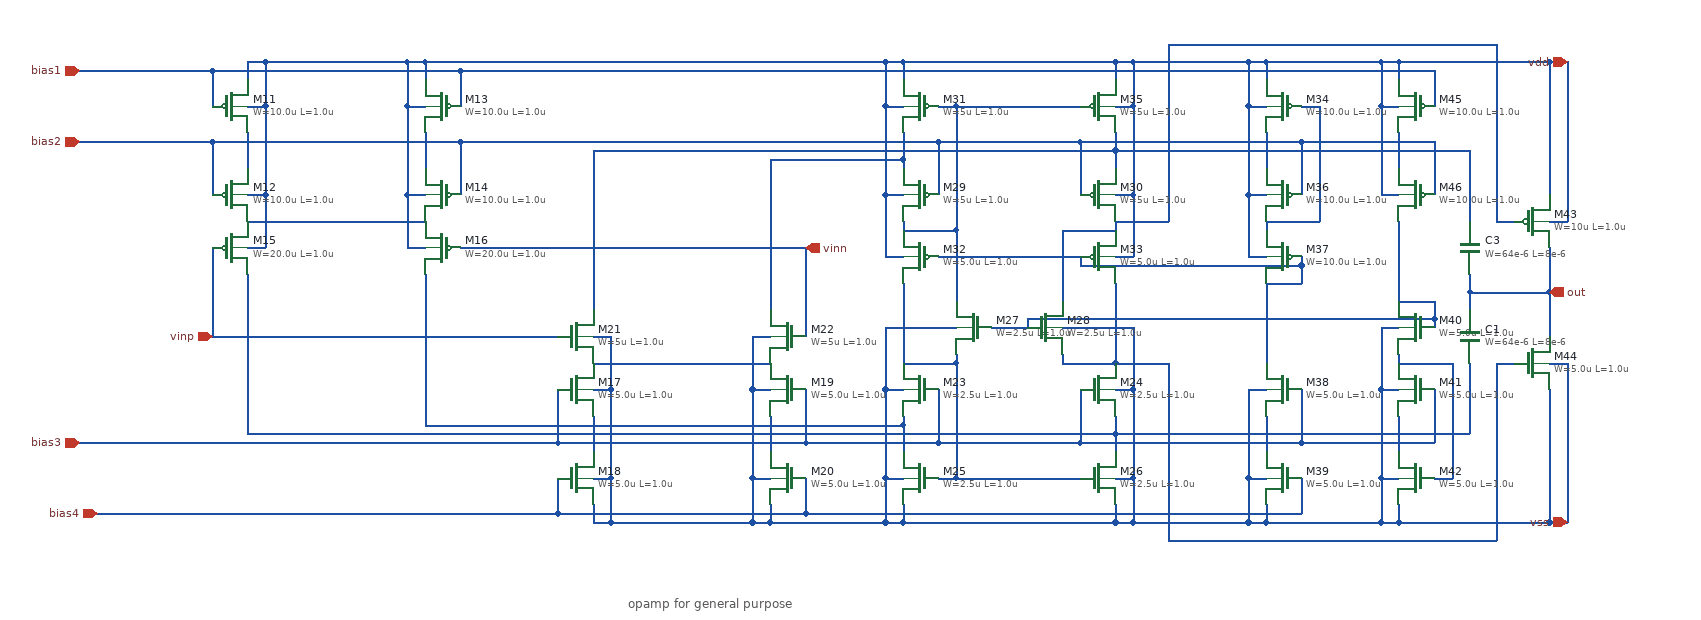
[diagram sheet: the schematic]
v {xschem version=3.4.7 file_version=1.2}
G {}
K {}
V {}
S {}
E {}
T {opamp for general purpose} 1180 0 2 0 0.4 0.4 {}
N 750 -390 770 -390 {
lab=vdd}
N 930 -390 950 -390 {
lab=vdd}
N 750 -600 750 -580 {
lab=vdd}
N 750 -550 770 -550 {
lab=vdd}
N 710 -590 710 -550 {
lab=bias1}
N 1470 -130 1470 -80 {
lab=vss}
N 1470 -130 1490 -130 {
lab=vss}
N 1490 -100 1490 -80 {
lab=vss}
N 1490 -600 1490 -580 {
lab=vdd}
N 1470 -550 1490 -550 {
lab=vdd}
N 1730 -600 1730 -580 {
lab=vdd}
N 1730 -550 1750 -550 {
lab=vdd}
N 1750 -550 1750 -450 {
lab=vdd}
N 1730 -130 1750 -130 {
lab=vss}
N 1730 -100 1730 -80 {
lab=vss}
N 710 -390 710 -290 {
lab=vinp}
N 1320 -290 1340 -290 {
lab=vss}
N 1140 -230 1160 -230 {
lab=vss}
N 1160 -130 1160 -80 {
lab=vss}
N 1140 -130 1160 -130 {
lab=vss}
N 1140 -200 1140 -160 {
lab=#net1}
N 1140 -100 1140 -80 {
lab=vss}
N 1100 -130 1100 -90 {
lab=bias4}
N 1100 -230 1100 -170 {
lab=bias3}
N 750 -450 770 -450 {
lab=vdd}
N 750 -520 750 -480 {
lab=#net2}
N 710 -510 710 -450 {
lab=bias2}
N 1470 -550 1470 -450 {
lab=vdd}
N 1470 -450 1490 -450 {
lab=vdd}
N 1490 -490 1490 -480 {
lab=#net3}
N 1470 -230 1490 -230 {
lab=vss}
N 1470 -230 1470 -130 {
lab=vss}
N 1490 -190 1490 -160 {
lab=#net4}
N 1730 -180 1730 -160 {
lab=#net5}
N 1730 -230 1750 -230 {
lab=vss}
N 990 -390 1380 -390 {
lab=vinn}
N 1380 -390 1380 -290 {
lab=vinn}
N 1730 -450 1750 -450 {
lab=vdd}
N 1730 -500 1730 -480 {
lab=#net6}
N 750 -420 950 -420 {
lab=#net7}
N 710 -290 1100 -290 {
lab=vinp}
N 1140 -260 1340 -260 {
lab=#net8}
N 1490 -420 1490 -410 {
lab=#net9}
N 1470 -380 1490 -380 {
lab=vdd}
N 1470 -450 1470 -380 {
lab=vdd}
N 1550 -130 1690 -130 {
lab=#net10}
N 1750 -130 1750 -80 {
lab=vss}
N 1590 -300 1630 -300 {
lab=#net11}
N 1730 -380 1750 -380 {
lab=vdd}
N 1750 -450 1750 -380 {
lab=vdd}
N 1730 -420 1730 -410 {
lab=#net12}
N 1670 -300 1750 -300 {
lab=vss}
N 1750 -300 1750 -230 {
lab=vss}
N 2220 -340 2220 -290 {
lab=out}
N 2220 -420 2240 -420 {
lab=vdd}
N 2240 -600 2240 -420 {
lab=vdd}
N 1900 -600 2030 -600 {
lab=vdd}
N 2220 -260 2240 -260 {
lab=vss}
N 2240 -260 2240 -80 {
lab=vss}
N 2220 -230 2220 -80 {
lab=vss}
N 2220 -600 2220 -450 {
lab=vdd}
N 1880 -550 1900 -550 {
lab=vdd}
N 1880 -600 1880 -550 {
lab=vdd}
N 1900 -600 1900 -580 {
lab=vdd}
N 1900 -520 1900 -480 {
lab=#net13}
N 1880 -450 1900 -450 {
lab=vdd}
N 1880 -550 1880 -450 {
lab=vdd}
N 1900 -420 1900 -410 {
lab=#net14}
N 1880 -380 1900 -380 {
lab=vdd}
N 1880 -450 1880 -380 {
lab=vdd}
N 1880 -230 1900 -230 {
lab=vss}
N 1880 -130 1880 -80 {
lab=vss}
N 1880 -130 1900 -130 {
lab=vss}
N 1900 -200 1900 -160 {
lab=#net15}
N 1900 -100 1900 -80 {
lab=vss}
N 1940 -130 1940 -90 {
lab=bias4}
N 1940 -230 1940 -170 {
lab=bias3}
N 2030 -550 2050 -550 {
lab=vdd}
N 2030 -600 2030 -550 {
lab=vdd}
N 2050 -600 2050 -580 {
lab=vdd}
N 2050 -520 2050 -480 {
lab=#net16}
N 2030 -450 2050 -450 {
lab=vdd}
N 2030 -550 2030 -450 {
lab=vdd}
N 2030 -230 2050 -230 {
lab=vss}
N 2030 -130 2030 -80 {
lab=vss}
N 2030 -130 2050 -130 {
lab=vss}
N 2050 -200 2050 -160 {
lab=#net17}
N 2050 -100 2050 -80 {
lab=vss}
N 2050 -270 2050 -260 {
lab=#net18}
N 2030 -300 2050 -300 {
lab=vss}
N 2030 -300 2030 -230 {
lab=vss}
N 2050 -600 2220 -600 {
lab=vdd}
N 950 -600 950 -580 {
lab=vdd}
N 930 -550 950 -550 {
lab=vdd}
N 990 -590 990 -550 {
lab=bias1}
N 930 -450 950 -450 {
lab=vdd}
N 950 -520 950 -480 {
lab=#net19}
N 990 -510 990 -450 {
lab=bias2}
N 1320 -230 1340 -230 {
lab=vss}
N 1320 -130 1340 -130 {
lab=vss}
N 1340 -200 1340 -160 {
lab=#net20}
N 1340 -100 1340 -80 {
lab=vss}
N 1380 -130 1380 -90 {
lab=bias4}
N 1380 -230 1380 -170 {
lab=bias3}
N 1140 -290 1160 -290 {
lab=vss}
N 1940 -510 1940 -450 {
lab=bias2}
N 1940 -550 1960 -550 {
lab=#net14}
N 1960 -550 1960 -420 {
lab=#net14}
N 1900 -420 1960 -420 {
lab=#net14}
N 1940 -370 1940 -350 {
lab=#net21}
N 1900 -350 1940 -350 {
lab=#net21}
N 1900 -350 1900 -260 {
lab=#net21}
N 2090 -590 2090 -550 {
lab=bias1}
N 2090 -510 2090 -450 {
lab=bias2}
N 1690 -170 1940 -170 {
lab=bias3}
N 2090 -230 2090 -170 {
lab=bias3}
N 2090 -130 2110 -130 {
lab=#net18}
N 2110 -260 2110 -130 {
lab=#net18}
N 2050 -260 2110 -260 {
lab=#net18}
N 2090 -310 2090 -300 {
lab=#net11}
N 2050 -330 2090 -330 {
lab=#net11}
N 2050 -420 2050 -330 {
lab=#net11}
N 1550 -550 1690 -550 {
lab=#net9}
N 1530 -510 1530 -450 {
lab=bias2}
N 1690 -510 1690 -450 {
lab=bias2}
N 1530 -380 1690 -380 {
lab=#net21}
N 1490 -350 1490 -260 {
lab=#net10}
N 1550 -270 1550 -260 {
lab=#net10}
N 1490 -260 1550 -260 {
lab=#net10}
N 1670 -270 1670 -260 {
lab=#net22}
N 1670 -260 1730 -260 {
lab=#net22}
N 1470 -300 1550 -300 {
lab=vss}
N 1470 -300 1470 -230 {
lab=vss}
N 1730 -350 1730 -260 {
lab=#net22}
N 1550 -410 1550 -330 {
lab=#net9}
N 1490 -410 1550 -410 {
lab=#net9}
N 1670 -410 1670 -330 {
lab=#net12}
N 1670 -410 1730 -410 {
lab=#net12}
N 1940 -510 2090 -510 {
lab=bias2}
N 1380 -90 1940 -90 {
lab=bias4}
N 1940 -170 2090 -170 {
lab=bias3}
N 1690 -370 1940 -370 {
lab=#net21}
N 1690 -380 1690 -370 {
lab=#net21}
N 1630 -310 2090 -310 {
lab=#net11}
N 1630 -310 1630 -300 {
lab=#net11}
N 750 -360 750 -180 {
lab=#net5}
N 950 -360 950 -190 {
lab=#net4}
N 1140 -500 1140 -320 {
lab=#net6}
N 1340 -490 1340 -320 {
lab=#net3}
N 1530 -230 1530 -170 {
lab=bias3}
N 1690 -230 1690 -170 {
lab=bias3}
N 1550 -260 1550 -130 {
lab=#net10}
N 1550 -550 1550 -410 {
lab=#net9}
N 2220 -600 2240 -600 {
lab=vdd}
N 2160 -420 2180 -420 {
lab=#net12}
N 2160 -620 2160 -420 {
lab=#net12}
N 1790 -620 2160 -620 {
lab=#net12}
N 1790 -620 1790 -420 {
lab=#net12}
N 1730 -420 1790 -420 {
lab=#net12}
N 2160 -260 2180 -260 {
lab=#net22}
N 2160 -260 2160 -60 {
lab=#net22}
N 1790 -60 2160 -60 {
lab=#net22}
N 1790 -260 1790 -60 {
lab=#net22}
N 1730 -260 1790 -260 {
lab=#net22}
N 1730 -180 2130 -180 {
lab=#net5}
N 2130 -340 2130 -320 {
lab=out}
N 1140 -500 1730 -500 {
lab=#net6}
N 1340 -490 1490 -490 {
lab=#net3}
N 950 -190 1490 -190 {
lab=#net4}
N 750 -180 1730 -180 {
lab=#net5}
N 1470 -600 1490 -600 {
lab=vdd}
N 1730 -600 1750 -600 {
lab=vdd}
N 2220 -80 2240 -80 {
lab=vss}
N 1100 -170 1380 -170 {
lab=bias3}
N 1100 -90 1380 -90 {
lab=bias4}
N 710 -590 990 -590 {
lab=bias1}
N 710 -510 990 -510 {
lab=bias2}
N 1690 -510 1940 -510 {
lab=bias2}
N 990 -590 2090 -590 {
lab=bias1}
N 930 -600 950 -600 {
lab=vdd}
N 560 -590 710 -590 {
lab=bias1}
N 560 -510 710 -510 {
lab=bias2}
N 560 -170 1100 -170 {
lab=bias3}
N 580 -90 1100 -90 {
lab=bias4}
N 2130 -340 2220 -340 {
lab=out}
N 2130 -260 2130 -180 {
lab=#net5}
N 1730 -500 2130 -500 {
lab=#net6}
N 2130 -500 2130 -420 {
lab=#net6}
N 2130 -360 2130 -340 {
lab=out}
N 930 -550 930 -450 {
lab=vdd}
N 770 -550 770 -450 {
lab=vdd}
N 1320 -130 1320 -80 {
lab=vss}
N 1160 -290 1160 -230 {
lab=vss}
N 1320 -290 1320 -230 {
lab=vss}
N 770 -450 770 -390 {
lab=vdd}
N 930 -450 930 -390 {
lab=vdd}
N 770 -600 770 -550 {
lab=vdd}
N 1340 -80 1470 -80 {
lab=vss}
N 1470 -80 1490 -80 {
lab=vss}
N 1470 -600 1470 -550 {
lab=vdd}
N 1490 -600 1730 -600 {
lab=vdd}
N 1750 -600 1750 -550 {
lab=vdd}
N 1750 -230 1750 -130 {
lab=vss}
N 1490 -80 1730 -80 {
lab=vss}
N 1140 -80 1160 -80 {
lab=vss}
N 1160 -230 1160 -130 {
lab=vss}
N 1730 -80 1750 -80 {
lab=vss}
N 2050 -80 2220 -80 {
lab=vss}
N 1750 -600 1880 -600 {
lab=vdd}
N 1880 -600 1900 -600 {
lab=vdd}
N 1750 -80 1880 -80 {
lab=vss}
N 1880 -230 1880 -130 {
lab=vss}
N 1880 -80 1900 -80 {
lab=vss}
N 2030 -600 2050 -600 {
lab=vdd}
N 1900 -80 2030 -80 {
lab=vss}
N 2030 -230 2030 -130 {
lab=vss}
N 2030 -80 2050 -80 {
lab=vss}
N 930 -600 930 -550 {
lab=vdd}
N 1320 -230 1320 -130 {
lab=vss}
N 1320 -80 1340 -80 {
lab=vss}
N 990 -510 1530 -510 {
lab=bias2}
N 1530 -510 1690 -510 {
lab=bias2}
N 1940 -380 1940 -370 {
lab=#net21}
N 2090 -330 2090 -310 {
lab=#net11}
N 1380 -170 1530 -170 {
lab=bias3}
N 1530 -170 1690 -170 {
lab=bias3}
N 1530 -130 1550 -130 {
lab=#net10}
N 1530 -550 1550 -550 {
lab=#net9}
N 1730 -200 1730 -180 {
lab=#net5}
N 1730 -520 1730 -500 {
lab=#net6}
N 1490 -520 1490 -490 {
lab=#net3}
N 1490 -200 1490 -190 {
lab=#net4}
N 2220 -390 2220 -340 {
lab=out}
N 1160 -80 1320 -80 {
lab=vss}
N 750 -600 770 -600 {
lab=vdd}
N 950 -600 1470 -600 {
lab=vdd}
N 770 -600 930 -600 {
lab=vdd}
C {devices/opin.sym} 2220 -340 0 0 {name=p1 lab=out}
C {devices/iopin.sym} 2240 -600 0 0 {name=p3 lab=vdd}
C {devices/iopin.sym} 2240 -80 0 0 {name=p4 lab=vss}
C {devices/ipin.sym} 710 -290 0 0 {name=p2 lab=vinp}
C {devices/ipin.sym} 1380 -390 0 1 {name=p5 lab=vinn}
C {symbols/pfet_06v0.sym} 730 -550 0 0 {name=M11
L=1.0u
W=10.0u
nf=1
m=1
ad="'int((nf+1)/2) * W/nf * 0.18u'"
pd="'2*int((nf+1)/2) * (W/nf + 0.18u)'"
as="'int((nf+2)/2) * W/nf * 0.18u'"
ps="'2*int((nf+2)/2) * (W/nf + 0.18u)'"
nrd="'0.18u / W'" nrs="'0.18u / W'"
sa=0 sb=0 sd=0
model=pfet_06v0
spiceprefix=X
}
C {symbols/pfet_06v0.sym} 730 -450 0 0 {name=M12
L=1.0u
W=10.0u
nf=1
m=1
ad="'int((nf+1)/2) * W/nf * 0.18u'"
pd="'2*int((nf+1)/2) * (W/nf + 0.18u)'"
as="'int((nf+2)/2) * W/nf * 0.18u'"
ps="'2*int((nf+2)/2) * (W/nf + 0.18u)'"
nrd="'0.18u / W'" nrs="'0.18u / W'"
sa=0 sb=0 sd=0
model=pfet_06v0
spiceprefix=X
}
C {symbols/pfet_06v0.sym} 970 -550 0 1 {name=M13
L=1.0u
W=10.0u
nf=1
m=1
ad="'int((nf+1)/2) * W/nf * 0.18u'"
pd="'2*int((nf+1)/2) * (W/nf + 0.18u)'"
as="'int((nf+2)/2) * W/nf * 0.18u'"
ps="'2*int((nf+2)/2) * (W/nf + 0.18u)'"
nrd="'0.18u / W'" nrs="'0.18u / W'"
sa=0 sb=0 sd=0
model=pfet_06v0
spiceprefix=X
}
C {symbols/pfet_06v0.sym} 970 -450 0 1 {name=M14
L=1.0u
W=10.0u
nf=1
m=1
ad="'int((nf+1)/2) * W/nf * 0.18u'"
pd="'2*int((nf+1)/2) * (W/nf + 0.18u)'"
as="'int((nf+2)/2) * W/nf * 0.18u'"
ps="'2*int((nf+2)/2) * (W/nf + 0.18u)'"
nrd="'0.18u / W'" nrs="'0.18u / W'"
sa=0 sb=0 sd=0
model=pfet_06v0
spiceprefix=X
}
C {symbols/pfet_06v0.sym} 730 -390 0 0 {name=M15
L=1.0u
W=20.0u
nf=2
m=1
ad="'int((nf+1)/2) * W/nf * 0.18u'"
pd="'2*int((nf+1)/2) * (W/nf + 0.18u)'"
as="'int((nf+2)/2) * W/nf * 0.18u'"
ps="'2*int((nf+2)/2) * (W/nf + 0.18u)'"
nrd="'0.18u / W'" nrs="'0.18u / W'"
sa=0 sb=0 sd=0
model=pfet_06v0
spiceprefix=X
}
C {symbols/pfet_06v0.sym} 970 -390 0 1 {name=M16
L=1.0u
W=20.0u
nf=2
m=1
ad="'int((nf+1)/2) * W/nf * 0.18u'"
pd="'2*int((nf+1)/2) * (W/nf + 0.18u)'"
as="'int((nf+2)/2) * W/nf * 0.18u'"
ps="'2*int((nf+2)/2) * (W/nf + 0.18u)'"
nrd="'0.18u / W'" nrs="'0.18u / W'"
sa=0 sb=0 sd=0
model=pfet_06v0
spiceprefix=X
}
C {symbols/nfet_06v0.sym} 1120 -230 0 0 {name=M17
L=1.0u
W=5.0u
nf=1
m=1
ad="'int((nf+1)/2) * W/nf * 0.18u'"
pd="'2*int((nf+1)/2) * (W/nf + 0.18u)'"
as="'int((nf+2)/2) * W/nf * 0.18u'"
ps="'2*int((nf+2)/2) * (W/nf + 0.18u)'"
nrd="'0.18u / W'" nrs="'0.18u / W'"
sa=0 sb=0 sd=0
model=nfet_06v0
spiceprefix=X
}
C {symbols/nfet_06v0.sym} 1120 -130 0 0 {name=M18
L=1.0u
W=5.0u
nf=1
m=1
ad="'int((nf+1)/2) * W/nf * 0.18u'"
pd="'2*int((nf+1)/2) * (W/nf + 0.18u)'"
as="'int((nf+2)/2) * W/nf * 0.18u'"
ps="'2*int((nf+2)/2) * (W/nf + 0.18u)'"
nrd="'0.18u / W'" nrs="'0.18u / W'"
sa=0 sb=0 sd=0
model=nfet_06v0
spiceprefix=X
}
C {symbols/nfet_06v0.sym} 1360 -230 0 1 {name=M19
L=1.0u
W=5.0u
nf=1
m=1
ad="'int((nf+1)/2) * W/nf * 0.18u'"
pd="'2*int((nf+1)/2) * (W/nf + 0.18u)'"
as="'int((nf+2)/2) * W/nf * 0.18u'"
ps="'2*int((nf+2)/2) * (W/nf + 0.18u)'"
nrd="'0.18u / W'" nrs="'0.18u / W'"
sa=0 sb=0 sd=0
model=nfet_06v0
spiceprefix=X
}
C {symbols/nfet_06v0.sym} 1360 -130 0 1 {name=M20
L=1.0u
W=5.0u
nf=1
m=1
ad="'int((nf+1)/2) * W/nf * 0.18u'"
pd="'2*int((nf+1)/2) * (W/nf + 0.18u)'"
as="'int((nf+2)/2) * W/nf * 0.18u'"
ps="'2*int((nf+2)/2) * (W/nf + 0.18u)'"
nrd="'0.18u / W'" nrs="'0.18u / W'"
sa=0 sb=0 sd=0
model=nfet_06v0
spiceprefix=X
}
C {symbols/nfet_06v0.sym} 1120 -290 0 0 {name=M21
L=1.0u
W=5u
nf=2
m=1
ad="'int((nf+1)/2) * W/nf * 0.18u'"
pd="'2*int((nf+1)/2) * (W/nf + 0.18u)'"
as="'int((nf+2)/2) * W/nf * 0.18u'"
ps="'2*int((nf+2)/2) * (W/nf + 0.18u)'"
nrd="'0.18u / W'" nrs="'0.18u / W'"
sa=0 sb=0 sd=0
model=nfet_06v0
spiceprefix=X
}
C {symbols/nfet_06v0.sym} 1360 -290 0 1 {name=M22
L=1.0u
W=5u
nf=2
m=1
ad="'int((nf+1)/2) * W/nf * 0.18u'"
pd="'2*int((nf+1)/2) * (W/nf + 0.18u)'"
as="'int((nf+2)/2) * W/nf * 0.18u'"
ps="'2*int((nf+2)/2) * (W/nf + 0.18u)'"
nrd="'0.18u / W'" nrs="'0.18u / W'"
sa=0 sb=0 sd=0
model=nfet_06v0
spiceprefix=X
}
C {symbols/pfet_06v0.sym} 1510 -450 0 1 {name=M29
L=1.0u
W=5u
nf=2
m=1
ad="'int((nf+1)/2) * W/nf * 0.18u'"
pd="'2*int((nf+1)/2) * (W/nf + 0.18u)'"
as="'int((nf+2)/2) * W/nf * 0.18u'"
ps="'2*int((nf+2)/2) * (W/nf + 0.18u)'"
nrd="'0.18u / W'" nrs="'0.18u / W'"
sa=0 sb=0 sd=0
model=pfet_06v0
spiceprefix=X
}
C {symbols/pfet_06v0.sym} 1710 -450 0 0 {name=M30
L=1.0u
W=5u
nf=2
m=1
ad="'int((nf+1)/2) * W/nf * 0.18u'"
pd="'2*int((nf+1)/2) * (W/nf + 0.18u)'"
as="'int((nf+2)/2) * W/nf * 0.18u'"
ps="'2*int((nf+2)/2) * (W/nf + 0.18u)'"
nrd="'0.18u / W'" nrs="'0.18u / W'"
sa=0 sb=0 sd=0
model=pfet_06v0
spiceprefix=X
}
C {symbols/pfet_06v0.sym} 1510 -550 0 1 {name=M31
L=1.0u
W=5u
nf=4
m=1
ad="'int((nf+1)/2) * W/nf * 0.18u'"
pd="'2*int((nf+1)/2) * (W/nf + 0.18u)'"
as="'int((nf+2)/2) * W/nf * 0.18u'"
ps="'2*int((nf+2)/2) * (W/nf + 0.18u)'"
nrd="'0.18u / W'" nrs="'0.18u / W'"
sa=0 sb=0 sd=0
model=pfet_06v0
spiceprefix=X
}
C {symbols/pfet_06v0.sym} 1710 -550 0 0 {name=M35
L=1.0u
W=5u
nf=4
m=1
ad="'int((nf+1)/2) * W/nf * 0.18u'"
pd="'2*int((nf+1)/2) * (W/nf + 0.18u)'"
as="'int((nf+2)/2) * W/nf * 0.18u'"
ps="'2*int((nf+2)/2) * (W/nf + 0.18u)'"
nrd="'0.18u / W'" nrs="'0.18u / W'"
sa=0 sb=0 sd=0
model=pfet_06v0
spiceprefix=X
}
C {symbols/pfet_06v0.sym} 1510 -380 0 1 {name=M32
L=1.0u
W=5.0u
nf=2
m=1
ad="'int((nf+1)/2) * W/nf * 0.18u'"
pd="'2*int((nf+1)/2) * (W/nf + 0.18u)'"
as="'int((nf+2)/2) * W/nf * 0.18u'"
ps="'2*int((nf+2)/2) * (W/nf + 0.18u)'"
nrd="'0.18u / W'" nrs="'0.18u / W'"
sa=0 sb=0 sd=0
model=pfet_06v0
spiceprefix=X
}
C {symbols/pfet_06v0.sym} 1710 -380 0 0 {name=M33
L=1.0u
W=5.0u
nf=2
m=1
ad="'int((nf+1)/2) * W/nf * 0.18u'"
pd="'2*int((nf+1)/2) * (W/nf + 0.18u)'"
as="'int((nf+2)/2) * W/nf * 0.18u'"
ps="'2*int((nf+2)/2) * (W/nf + 0.18u)'"
nrd="'0.18u / W'" nrs="'0.18u / W'"
sa=0 sb=0 sd=0
model=pfet_06v0
spiceprefix=X
}
C {symbols/nfet_06v0.sym} 1510 -230 0 1 {name=M23
L=1.0u
W=2.5u
nf=2
m=1
ad="'int((nf+1)/2) * W/nf * 0.18u'"
pd="'2*int((nf+1)/2) * (W/nf + 0.18u)'"
as="'int((nf+2)/2) * W/nf * 0.18u'"
ps="'2*int((nf+2)/2) * (W/nf + 0.18u)'"
nrd="'0.18u / W'" nrs="'0.18u / W'"
sa=0 sb=0 sd=0
model=nfet_06v0
spiceprefix=X
}
C {symbols/nfet_06v0.sym} 1710 -230 0 0 {name=M24
L=1.0u
W=2.5u
nf=2
m=1
ad="'int((nf+1)/2) * W/nf * 0.18u'"
pd="'2*int((nf+1)/2) * (W/nf + 0.18u)'"
as="'int((nf+2)/2) * W/nf * 0.18u'"
ps="'2*int((nf+2)/2) * (W/nf + 0.18u)'"
nrd="'0.18u / W'" nrs="'0.18u / W'"
sa=0 sb=0 sd=0
model=nfet_06v0
spiceprefix=X
}
C {symbols/nfet_06v0.sym} 1510 -130 0 1 {name=M25
L=1.0u
W=2.5u
nf=4
m=1
ad="'int((nf+1)/2) * W/nf * 0.18u'"
pd="'2*int((nf+1)/2) * (W/nf + 0.18u)'"
as="'int((nf+2)/2) * W/nf * 0.18u'"
ps="'2*int((nf+2)/2) * (W/nf + 0.18u)'"
nrd="'0.18u / W'" nrs="'0.18u / W'"
sa=0 sb=0 sd=0
model=nfet_06v0
spiceprefix=X
}
C {symbols/nfet_06v0.sym} 1710 -130 0 0 {name=M26
L=1.0u
W=2.5u
nf=4
m=1
ad="'int((nf+1)/2) * W/nf * 0.18u'"
pd="'2*int((nf+1)/2) * (W/nf + 0.18u)'"
as="'int((nf+2)/2) * W/nf * 0.18u'"
ps="'2*int((nf+2)/2) * (W/nf + 0.18u)'"
nrd="'0.18u / W'" nrs="'0.18u / W'"
sa=0 sb=0 sd=0
model=nfet_06v0
spiceprefix=X
}
C {symbols/nfet_06v0.sym} 1570 -300 0 1 {name=M27
L=1.0u
W=2.5u
nf=1
m=1
ad="'int((nf+1)/2) * W/nf * 0.18u'"
pd="'2*int((nf+1)/2) * (W/nf + 0.18u)'"
as="'int((nf+2)/2) * W/nf * 0.18u'"
ps="'2*int((nf+2)/2) * (W/nf + 0.18u)'"
nrd="'0.18u / W'" nrs="'0.18u / W'"
sa=0 sb=0 sd=0
model=nfet_06v0
spiceprefix=X
}
C {symbols/nfet_06v0.sym} 1650 -300 0 0 {name=M28
L=1.0u
W=2.5u
nf=1
m=1
ad="'int((nf+1)/2) * W/nf * 0.18u'"
pd="'2*int((nf+1)/2) * (W/nf + 0.18u)'"
as="'int((nf+2)/2) * W/nf * 0.18u'"
ps="'2*int((nf+2)/2) * (W/nf + 0.18u)'"
nrd="'0.18u / W'" nrs="'0.18u / W'"
sa=0 sb=0 sd=0
model=nfet_06v0
spiceprefix=X
}
C {symbols/pfet_06v0.sym} 1920 -550 0 1 {name=M34
L=1.0u
W=10.0u
nf=1
m=1
ad="'int((nf+1)/2) * W/nf * 0.18u'"
pd="'2*int((nf+1)/2) * (W/nf + 0.18u)'"
as="'int((nf+2)/2) * W/nf * 0.18u'"
ps="'2*int((nf+2)/2) * (W/nf + 0.18u)'"
nrd="'0.18u / W'" nrs="'0.18u / W'"
sa=0 sb=0 sd=0
model=pfet_06v0
spiceprefix=X
}
C {symbols/pfet_06v0.sym} 1920 -450 0 1 {name=M36
L=1.0u
W=10.0u
nf=1
m=1
ad="'int((nf+1)/2) * W/nf * 0.18u'"
pd="'2*int((nf+1)/2) * (W/nf + 0.18u)'"
as="'int((nf+2)/2) * W/nf * 0.18u'"
ps="'2*int((nf+2)/2) * (W/nf + 0.18u)'"
nrd="'0.18u / W'" nrs="'0.18u / W'"
sa=0 sb=0 sd=0
model=pfet_06v0
spiceprefix=X
}
C {symbols/pfet_06v0.sym} 1920 -380 0 1 {name=M37
L=1.0u
W=10.0u
nf=1
m=1
ad="'int((nf+1)/2) * W/nf * 0.18u'"
pd="'2*int((nf+1)/2) * (W/nf + 0.18u)'"
as="'int((nf+2)/2) * W/nf * 0.18u'"
ps="'2*int((nf+2)/2) * (W/nf + 0.18u)'"
nrd="'0.18u / W'" nrs="'0.18u / W'"
sa=0 sb=0 sd=0
model=pfet_06v0
spiceprefix=X
}
C {symbols/nfet_06v0.sym} 1920 -230 0 1 {name=M38
L=1.0u
W=5.0u
nf=1
m=1
ad="'int((nf+1)/2) * W/nf * 0.18u'"
pd="'2*int((nf+1)/2) * (W/nf + 0.18u)'"
as="'int((nf+2)/2) * W/nf * 0.18u'"
ps="'2*int((nf+2)/2) * (W/nf + 0.18u)'"
nrd="'0.18u / W'" nrs="'0.18u / W'"
sa=0 sb=0 sd=0
model=nfet_06v0
spiceprefix=X
}
C {symbols/nfet_06v0.sym} 1920 -130 0 1 {name=M39
L=1.0u
W=5.0u
nf=1
m=1
ad="'int((nf+1)/2) * W/nf * 0.18u'"
pd="'2*int((nf+1)/2) * (W/nf + 0.18u)'"
as="'int((nf+2)/2) * W/nf * 0.18u'"
ps="'2*int((nf+2)/2) * (W/nf + 0.18u)'"
nrd="'0.18u / W'" nrs="'0.18u / W'"
sa=0 sb=0 sd=0
model=nfet_06v0
spiceprefix=X
}
C {symbols/pfet_06v0.sym} 2070 -550 0 1 {name=M45
L=1.0u
W=10.0u
nf=1
m=1
ad="'int((nf+1)/2) * W/nf * 0.18u'"
pd="'2*int((nf+1)/2) * (W/nf + 0.18u)'"
as="'int((nf+2)/2) * W/nf * 0.18u'"
ps="'2*int((nf+2)/2) * (W/nf + 0.18u)'"
nrd="'0.18u / W'" nrs="'0.18u / W'"
sa=0 sb=0 sd=0
model=pfet_06v0
spiceprefix=X
}
C {symbols/pfet_06v0.sym} 2070 -450 0 1 {name=M46
L=1.0u
W=10.0u
nf=1
m=1
ad="'int((nf+1)/2) * W/nf * 0.18u'"
pd="'2*int((nf+1)/2) * (W/nf + 0.18u)'"
as="'int((nf+2)/2) * W/nf * 0.18u'"
ps="'2*int((nf+2)/2) * (W/nf + 0.18u)'"
nrd="'0.18u / W'" nrs="'0.18u / W'"
sa=0 sb=0 sd=0
model=pfet_06v0
spiceprefix=X
}
C {symbols/nfet_06v0.sym} 2070 -300 0 1 {name=M40
L=1.0u
W=5.0u
nf=1
m=1
ad="'int((nf+1)/2) * W/nf * 0.18u'"
pd="'2*int((nf+1)/2) * (W/nf + 0.18u)'"
as="'int((nf+2)/2) * W/nf * 0.18u'"
ps="'2*int((nf+2)/2) * (W/nf + 0.18u)'"
nrd="'0.18u / W'" nrs="'0.18u / W'"
sa=0 sb=0 sd=0
model=nfet_06v0
spiceprefix=X
}
C {symbols/nfet_06v0.sym} 2070 -230 0 1 {name=M41
L=1.0u
W=5.0u
nf=1
m=1
ad="'int((nf+1)/2) * W/nf * 0.18u'"
pd="'2*int((nf+1)/2) * (W/nf + 0.18u)'"
as="'int((nf+2)/2) * W/nf * 0.18u'"
ps="'2*int((nf+2)/2) * (W/nf + 0.18u)'"
nrd="'0.18u / W'" nrs="'0.18u / W'"
sa=0 sb=0 sd=0
model=nfet_06v0
spiceprefix=X
}
C {symbols/nfet_06v0.sym} 2070 -130 0 1 {name=M42
L=1.0u
W=5.0u
nf=1
m=1
ad="'int((nf+1)/2) * W/nf * 0.18u'"
pd="'2*int((nf+1)/2) * (W/nf + 0.18u)'"
as="'int((nf+2)/2) * W/nf * 0.18u'"
ps="'2*int((nf+2)/2) * (W/nf + 0.18u)'"
nrd="'0.18u / W'" nrs="'0.18u / W'"
sa=0 sb=0 sd=0
model=nfet_06v0
spiceprefix=X
}
C {symbols/pfet_06v0.sym} 2200 -420 0 0 {name=M43
L=1.0u
W=10u
nf=10
m=1
ad="'int((nf+1)/2) * W/nf * 0.18u'"
pd="'2*int((nf+1)/2) * (W/nf + 0.18u)'"
as="'int((nf+2)/2) * W/nf * 0.18u'"
ps="'2*int((nf+2)/2) * (W/nf + 0.18u)'"
nrd="'0.18u / W'" nrs="'0.18u / W'"
sa=0 sb=0 sd=0
model=pfet_06v0
spiceprefix=X
}
C {symbols/nfet_06v0.sym} 2200 -260 0 0 {name=M44
L=1.0u
W=5.0u
nf=10
m=1
ad="'int((nf+1)/2) * W/nf * 0.18u'"
pd="'2*int((nf+1)/2) * (W/nf + 0.18u)'"
as="'int((nf+2)/2) * W/nf * 0.18u'"
ps="'2*int((nf+2)/2) * (W/nf + 0.18u)'"
nrd="'0.18u / W'" nrs="'0.18u / W'"
sa=0 sb=0 sd=0
model=nfet_06v0
spiceprefix=X
}
C {symbols/cap_mim_2f0fF.sym} 2130 -390 0 0 {name=C3
W=64e-6
L=8e-6
model=cap_mim_2f0fF
spiceprefix=X
m=1}
C {symbols/cap_mim_2f0fF.sym} 2130 -290 0 0 {name=C1
W=64e-6
L=8e-6
model=cap_mim_2f0fF
spiceprefix=X
m=1}
C {devices/ipin.sym} 560 -590 0 0 {name=p6 lab=bias1}
C {devices/ipin.sym} 560 -510 0 0 {name=p7 lab=bias2
}
C {devices/ipin.sym} 560 -170 0 0 {name=p8 lab=bias3
}
C {devices/ipin.sym} 580 -90 0 0 {name=p9 lab=bias4}
